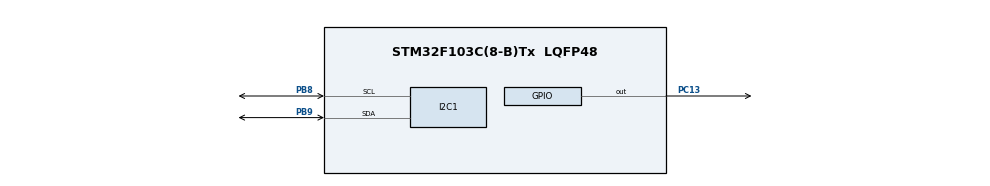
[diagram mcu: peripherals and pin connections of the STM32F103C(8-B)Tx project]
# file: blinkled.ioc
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Mcu.Family=STM32F1
Mcu.Name=STM32F103C(8-B)Tx
Mcu.Package=LQFP48
NVIC.PriorityGroup=NVIC_PRIORITYGROUP_4
PA13.Mode=Trace_Asynchronous_SW
PA13.Signal=SYS_JTMS-SWDIO
PA14.Mode=Trace_Asynchronous_SW
PA14.Signal=SYS_JTCK-SWCLK
PB3.Mode=Trace_Asynchronous_SW
PB3.Signal=SYS_JTDO-TRACESWO
PB8.Mode=I2C
PB8.Signal=I2C1_SCL
PB9.Mode=I2C
PB9.Signal=I2C1_SDA
PC13-TAMPER-RTC.Signal=GPIO_Output
PD0-OSC_IN.Mode=HSE-External-Oscillator
PD0-OSC_IN.Signal=RCC_OSC_IN
PD1-OSC_OUT.Mode=HSE-External-Oscillator
PD1-OSC_OUT.Signal=RCC_OSC_OUT
ProjectManager.HeapSize=0x200
ProjectManager.StackSize=0x400
ProjectManager.TargetToolchain=MDK-ARM V5
RCC.AHBFreq_Value=72000000
RCC.APB1CLKDivider=RCC_HCLK_DIV2
RCC.APB1Freq_Value=36000000
RCC.APB1TimFreq_Value=72000000
RCC.APB2Freq_Value=72000000
RCC.APB2TimFreq_Value=72000000
RCC.HCLKFreq_Value=72000000
RCC.PLLMUL=RCC_PLL_MUL9
RCC.PLLSourceVirtual=RCC_PLLSOURCE_HSE
RCC.SYSCLKFreq_VALUE=72000000
RCC.SYSCLKSource=RCC_SYSCLKSOURCE_PLLCLK
RCC.USBFreq_Value=72000000
board=custom

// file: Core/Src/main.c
/* USER CODE BEGIN Header */
/**
  ******************************************************************************
  * @file           : main.c
  * @brief          : Main program body
  ******************************************************************************
  * @attention
  *
  * Copyright (c) 2023 STMicroelectronics.
  * All rights reserved.
  *
  * This software is licensed under terms that can be found in the LICENSE file
  * in the root directory of this software component.
  * If no LICENSE file comes with this software, it is provided AS-IS.
  *
  ******************************************************************************
  */
/* USER CODE END Header */
#include "main.h"
#include "stdio.h"
#include "string.h"
#include "math.h"

I2C_HandleTypeDef hi2c1;

void SystemClock_Config(void);
static void MX_GPIO_Init(void);
static void MX_I2C1_Init(void);

/* USER CODE BEGIN 0 */
#define MPU6050_ADDR 0xD0

#define SMPLRT_DIV_REG 0x19
#define GYRO_CONFIG_REG 0x1B
#define ACCEL_CONFIG_REG 0x1C
#define ACCEL_XOUT_H_REG 0x3B
#define TEMP_OUT_H_REG 0x41
#define GYRO_XOUT_H_REG 0x43
#define PWR_MGMT_1_REG 0x6B
#define WHO_AM_I_REG 0x75

int16_t Accel_X_RAW, Accel_Y_RAW, Accel_Z_RAW;
int16_t Gyro_X_RAW, Gyro_Y_RAW, Gyro_Z_RAW;
float Ax, Ay, Az, Gx, Gy, Gz;
extern I2C_HandleTypeDef hi2c1;  // change your handler here accordingly
void MPU6050_init(void); //Initialize the MPU
void MPU6050_Read_Accel (float *Ax, float *Ay, float *Az); //Read MPU Accelerator
void MPU6050_Read_Gyro (float *Gx, float *Gy, float *Gz); //Read MPU Gyroscope
void lcd_init (void);   // initialize lcd

void lcd_send_cmd (char cmd);  // send command to the lcd
void lcd_send_data (char data);  // send data to the lcd
void lcd_send_string (char *str);  // send string to the lcd
void lcd_put_cur(int row, int col);  // put cursor at the entered position row (0 or 1), col (0-15);
void lcd_clear (void);

void MPU6050_init(void)
{
	uint8_t check,data;
	HAL_I2C_Mem_Read(&hi2c1, MPU6050_ADDR, WHO_AM_I_REG, 1, &check, 1 , 1000);
	if (check == 104)
	{
		//Power management register write all 0's to wake up sensor
		data = 0;
		HAL_I2C_Mem_Write(&hi2c1,MPU6050_ADDR, PWR_MGMT_1_REG, 1, &data, 1, 1000);
		//Set data rate of 1KHz by writing SMPRT_DIV register
		data = 0x07;
		HAL_I2C_Mem_Write(&hi2c1, MPU6050_ADDR, SMPLRT_DIV_REG, 1, &data, 1, 1000);
		//Writing both register with 0 to set full scale range
		data = 0x00;
		HAL_I2C_Mem_Write(&hi2c1, MPU6050_ADDR, ACCEL_CONFIG_REG, 1, &data, 1, 1000);

		data = 0x00;
		HAL_I2C_Mem_Write(&hi2c1, MPU6050_ADDR, GYRO_CONFIG_REG, 1, &data, 1, 1000);
	}

}

//Function with multiple return using pointer

void MPU6050_Read_Accel (float* Ax, float* Ay, float* Az)
{
	uint8_t Rec_Data[6];

	HAL_I2C_Mem_Read (&hi2c1, MPU6050_ADDR, ACCEL_XOUT_H_REG, 1, Rec_Data, 6, 1000);
	//Adding 2 BYTES into 16 bit integer
	Accel_X_RAW = (int16_t)(Rec_Data[0] << 8 | Rec_Data [1]);
	Accel_Y_RAW = (int16_t)(Rec_Data[2] << 8 | Rec_Data [3]);
	Accel_Z_RAW = (int16_t)(Rec_Data[4] << 8 | Rec_Data [5]);

	*Ax = Accel_X_RAW*100/16384.0;
	*Ay = Accel_Y_RAW*100/16384.0;
	*Az = Accel_Z_RAW*100/16384.0;
}
void MPU6050_Read_Gyro (float* Gx, float* Gy, float* Gz)
{
	uint8_t Rec_Data[6];
	HAL_I2C_Mem_Read (&hi2c1, MPU6050_ADDR, GYRO_XOUT_H_REG, 1, Rec_Data, 6, 1000);
	Gyro_X_RAW = (int16_t)(Rec_Data[0] << 8 | Rec_Data [1]);
	Gyro_Y_RAW = (int16_t)(Rec_Data[0] << 8 | Rec_Data [1]);
	Gyro_Z_RAW = (int16_t)(Rec_Data[0] << 8 | Rec_Data [1]);

	*Gx = Gyro_X_RAW/131.0;
	*Gy = Gyro_Y_RAW/131.0;
	*Gz = Gyro_Z_RAW/131.0;
}
/* USER CODE END 0 */

#define SLAVE_ADDRESS_LCD 0x4E // change this according to ur setup

void lcd_send_cmd (char cmd)
{
  char data_u, data_l;
	uint8_t data_t[4];
	data_u = (cmd&0xf0);
	data_l = ((cmd<<4)&0xf0);
	data_t[0] = data_u|0x0C;  //en=1, rs=0
	data_t[1] = data_u|0x08;  //en=0, rs=0
	data_t[2] = data_l|0x0C;  //en=1, rs=0
	data_t[3] = data_l|0x08;  //en=0, rs=0
	HAL_I2C_Master_Transmit (&hi2c1, SLAVE_ADDRESS_LCD,(uint8_t *) data_t, 4, 100);
}

void lcd_send_data (char data)
{
	char data_u, data_l;
	uint8_t data_t[4];
	data_u = (data&0xf0);
	data_l = ((data<<4)&0xf0);
	data_t[0] = data_u|0x0D;  //en=1, rs=0
	data_t[1] = data_u|0x09;  //en=0, rs=0
	data_t[2] = data_l|0x0D;  //en=1, rs=0
	data_t[3] = data_l|0x09;  //en=0, rs=0
	HAL_I2C_Master_Transmit (&hi2c1, SLAVE_ADDRESS_LCD,(uint8_t *) data_t, 4, 100);
}

void lcd_clear (void)
{
	lcd_send_cmd (0x80);
	for (int i=0; i<70; i++)
	{
		lcd_send_data (' ');
	}
}

void lcd_put_cur(int row, int col)
{
    switch (row)
    {
        case 0:
            col |= 0x80;
            break;
        case 1:
            col |= 0xC0;
            break;
    }

    lcd_send_cmd (col);
}

void lcd_init (void)
{
	// 4 bit initialisation
	HAL_Delay(50);  // wait for >40ms
	lcd_send_cmd (0x30);
	HAL_Delay(5);  // wait for >4.1ms
	lcd_send_cmd (0x30);
	HAL_Delay(1);  // wait for >100us
	lcd_send_cmd (0x30);
	HAL_Delay(10);
	lcd_send_cmd (0x20);  // 4bit mode
	HAL_Delay(10);

  // dislay initialisation
	lcd_send_cmd (0x28); // Function set --> DL=0 (4 bit mode), N = 1 (2 line display) F = 0 (5x8 characters)
	HAL_Delay(1);
	lcd_send_cmd (0x08); //Display on/off control --> D=0,C=0, B=0  ---> display off
	HAL_Delay(1);
	lcd_send_cmd (0x01);  // clear display
	HAL_Delay(1);
	HAL_Delay(1);
	lcd_send_cmd (0x06); //Entry mode set --> I/D = 1 (increment cursor) & S = 0 (no shift)
	HAL_Delay(1);
	lcd_send_cmd (0x0C); //Display on/off control --> D = 1, C and B = 0. (Cursor and blink, last two bits)
}

void lcd_send_string (char *str)
{
	while (*str) lcd_send_data (*str++);
}

int step_count = 0;
int is_step = 0;
float threshold = 140;

int step_counter(){
	float total_accel = sqrt(Ax * Ax + Ay * Ay + Az * Az);

  if (total_accel > threshold && !is_step) {
            step_count++;
            is_step = 1;
	}
	else if (total_accel < threshold && is_step) {
            is_step = 0;
  }
	return step_count;
}
float min = 999;
float max = 0;
float min_max(){
	float total_accel = sqrt(Ax * Ax + Ay * Ay + Az * Az);
	if (total_accel < min) min = total_accel;
	if (total_accel > max) max = total_accel;
	return 0;
}

int main(void)
{

  /* MCU Configuration--------------------------------------------------------*/

  /* Reset of all peripherals, Initializes the Flash interface and the Systick. */
  HAL_Init();

  /* Configure the system clock */
  SystemClock_Config();

  /* Initialize all configured peripherals */
		MX_GPIO_Init();
		MX_I2C1_Init();
  /* USER CODE BEGIN 2 */
	lcd_init();
	MPU6050_init();
  /* USER CODE END 2 */

  /* Infinite loop */
  while (1)
  {
		//float Ax, Ay, Az;
		HAL_GPIO_TogglePin(GPIOC, GPIO_PIN_13);
		MPU6050_Read_Accel(&Ax, &Ay, &Az);
		min_max();
		int step = step_counter();
		//MPU6050_Read_Gyro(&Gx, &Gy, &Gz);
		lcd_clear();
		lcd_put_cur(0,1);
		char str[8];
		sprintf(str, "%.0f", max);
		lcd_send_string(str);

		lcd_put_cur(0,8);
		char str1[4];
		sprintf(str1, "%.0f", min);
		lcd_send_string(str1);

		lcd_put_cur(1,0);
		char str2[4];
		sprintf(str2, "%d", step);
		lcd_send_string("step:");
		lcd_send_string(str2);

		HAL_Delay(10);

  }
}

void SystemClock_Config(void)
{
  RCC_OscInitTypeDef RCC_OscInitStruct = {0};
  RCC_ClkInitTypeDef RCC_ClkInitStruct = {0};

  /** Initializes the RCC Oscillators according to the specified parameters
  * in the RCC_OscInitTypeDef structure.
  */
  RCC_OscInitStruct.OscillatorType = RCC_OSCILLATORTYPE_HSI;
  RCC_OscInitStruct.HSIState = RCC_HSI_ON;
  RCC_OscInitStruct.HSICalibrationValue = RCC_HSICALIBRATION_DEFAULT;
  RCC_OscInitStruct.PLL.PLLState = RCC_PLL_ON;
  RCC_OscInitStruct.PLL.PLLSource = RCC_PLLSOURCE_HSI_DIV2;
  RCC_OscInitStruct.PLL.PLLMUL = RCC_PLL_MUL16;
  if (HAL_RCC_OscConfig(&RCC_OscInitStruct) != HAL_OK)
  {
    Error_Handler();
  }

  /** Initializes the CPU, AHB and APB buses clocks
  */
  RCC_ClkInitStruct.ClockType = RCC_CLOCKTYPE_HCLK|RCC_CLOCKTYPE_SYSCLK
                              |RCC_CLOCKTYPE_PCLK1|RCC_CLOCKTYPE_PCLK2;
  RCC_ClkInitStruct.SYSCLKSource = RCC_SYSCLKSOURCE_PLLCLK;
  RCC_ClkInitStruct.AHBCLKDivider = RCC_SYSCLK_DIV1;
  RCC_ClkInitStruct.APB1CLKDivider = RCC_HCLK_DIV2;
  RCC_ClkInitStruct.APB2CLKDivider = RCC_HCLK_DIV1;

  if (HAL_RCC_ClockConfig(&RCC_ClkInitStruct, FLASH_LATENCY_2) != HAL_OK)
  {
    Error_Handler();
  }
}

static void MX_I2C1_Init(void)
{

  hi2c1.Instance = I2C1;
  hi2c1.Init.ClockSpeed = 100000;
  hi2c1.Init.DutyCycle = I2C_DUTYCYCLE_2;
  hi2c1.Init.OwnAddress1 = 0;
  hi2c1.Init.AddressingMode = I2C_ADDRESSINGMODE_7BIT;
  hi2c1.Init.DualAddressMode = I2C_DUALADDRESS_DISABLE;
  hi2c1.Init.OwnAddress2 = 0;
  hi2c1.Init.GeneralCallMode = I2C_GENERALCALL_DISABLE;
  hi2c1.Init.NoStretchMode = I2C_NOSTRETCH_DISABLE;
  if (HAL_I2C_Init(&hi2c1) != HAL_OK)
  {
    Error_Handler();
  }

}

static void MX_GPIO_Init(void)
{
  GPIO_InitTypeDef GPIO_InitStruct = {0};

  /* GPIO Ports Clock Enable */
  __HAL_RCC_GPIOC_CLK_ENABLE();
  __HAL_RCC_GPIOA_CLK_ENABLE();
  __HAL_RCC_GPIOB_CLK_ENABLE();

  /*Configure GPIO pin Output Level */
  HAL_GPIO_WritePin(GPIOC, GPIO_PIN_13, GPIO_PIN_RESET);

  /*Configure GPIO pin : PC13 */
  GPIO_InitStruct.Pin = GPIO_PIN_13;
  GPIO_InitStruct.Mode = GPIO_MODE_OUTPUT_PP;
  GPIO_InitStruct.Pull = GPIO_NOPULL;
  GPIO_InitStruct.Speed = GPIO_SPEED_FREQ_LOW;
  HAL_GPIO_Init(GPIOC, &GPIO_InitStruct);

}

void Error_Handler(void)
{
  __disable_irq();
  while (1)
  {
  }
}
